One B-rep face of a CAD part: STEP entity #1670.
In plain terms, the planar face has unit normal (0, 1, 0).
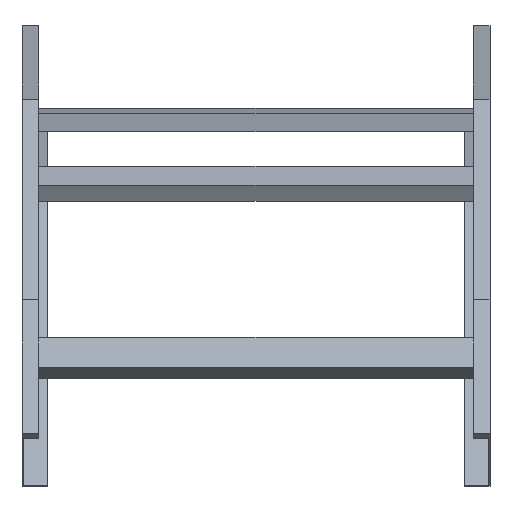
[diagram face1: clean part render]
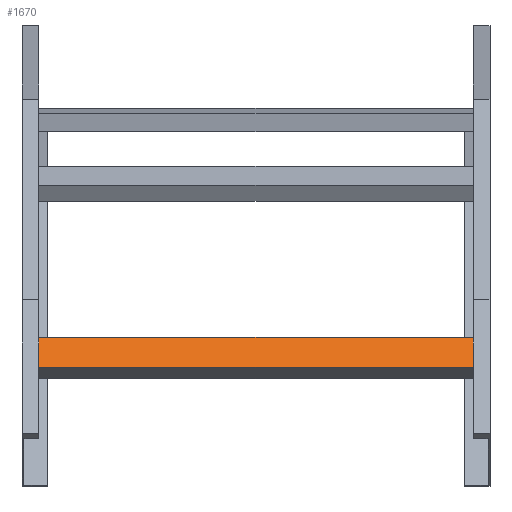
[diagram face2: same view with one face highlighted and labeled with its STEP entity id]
Its self-contained STEP definition (entity closure, numbers rounded to 3 decimals):
#4 = VECTOR ( 'NONE', #728, 1000. ) ;
#7 = AXIS2_PLACEMENT_3D ( 'NONE', #883, #1269, #544 ) ;
#79 = LINE ( 'NONE', #502, #1294 ) ;
#249 = CARTESIAN_POINT ( 'NONE',  ( 248., 20., 20.25 ) ) ;
#287 = DIRECTION ( 'NONE',  ( -1., 0., 0. ) ) ;
#348 = CARTESIAN_POINT ( 'NONE',  ( -248., 20., 20.25 ) ) ;
#427 = ORIENTED_EDGE ( 'NONE', *, *, #509, .F. ) ;
#438 = CARTESIAN_POINT ( 'NONE',  ( 248., 20., 20.25 ) ) ;
#466 = CARTESIAN_POINT ( 'NONE',  ( 248., 20., 20.25 ) ) ;
#484 = VERTEX_POINT ( 'NONE', #1605 ) ;
#502 = CARTESIAN_POINT ( 'NONE',  ( 248., 20., -20.25 ) ) ;
#509 = EDGE_CURVE ( 'NONE', #1320, #582, #1585, .T. ) ;
#531 = PLANE ( 'NONE',  #7 ) ;
#544 = DIRECTION ( 'NONE',  ( 0., 0., -1. ) ) ;
#582 = VERTEX_POINT ( 'NONE', #348 ) ;
#588 = VERTEX_POINT ( 'NONE', #848 ) ;
#591 = ORIENTED_EDGE ( 'NONE', *, *, #845, .T. ) ;
#605 = LINE ( 'NONE', #466, #4 ) ;
#634 = FACE_OUTER_BOUND ( 'NONE', #1105, .T. ) ;
#684 = EDGE_CURVE ( 'NONE', #588, #1320, #605, .T. ) ;
#728 = DIRECTION ( 'NONE',  ( 0., 0., 1. ) ) ;
#818 = VECTOR ( 'NONE', #287, 1000. ) ;
#845 = EDGE_CURVE ( 'NONE', #588, #484, #79, .T. ) ;
#848 = CARTESIAN_POINT ( 'NONE',  ( 248., 20., -20.25 ) ) ;
#883 = CARTESIAN_POINT ( 'NONE',  ( 248., 20., 20.25 ) ) ;
#983 = DIRECTION ( 'NONE',  ( -1., 0., 0. ) ) ;
#1025 = ORIENTED_EDGE ( 'NONE', *, *, #1357, .T. ) ;
#1105 = EDGE_LOOP ( 'NONE', ( #1025, #427, #1201, #591 ) ) ;
#1147 = CARTESIAN_POINT ( 'NONE',  ( -248., 20., 20.25 ) ) ;
#1201 = ORIENTED_EDGE ( 'NONE', *, *, #684, .F. ) ;
#1260 = DIRECTION ( 'NONE',  ( 0., 0., 1. ) ) ;
#1269 = DIRECTION ( 'NONE',  ( 0., -1., 0. ) ) ;
#1294 = VECTOR ( 'NONE', #983, 1000. ) ;
#1320 = VERTEX_POINT ( 'NONE', #249 ) ;
#1357 = EDGE_CURVE ( 'NONE', #484, #582, #1409, .T. ) ;
#1409 = LINE ( 'NONE', #1147, #1557 ) ;
#1557 = VECTOR ( 'NONE', #1260, 1000. ) ;
#1585 = LINE ( 'NONE', #438, #818 ) ;
#1605 = CARTESIAN_POINT ( 'NONE',  ( -248., 20., -20.25 ) ) ;
#1670 = ADVANCED_FACE ( 'NONE', ( #634 ), #531, .F. ) ;
